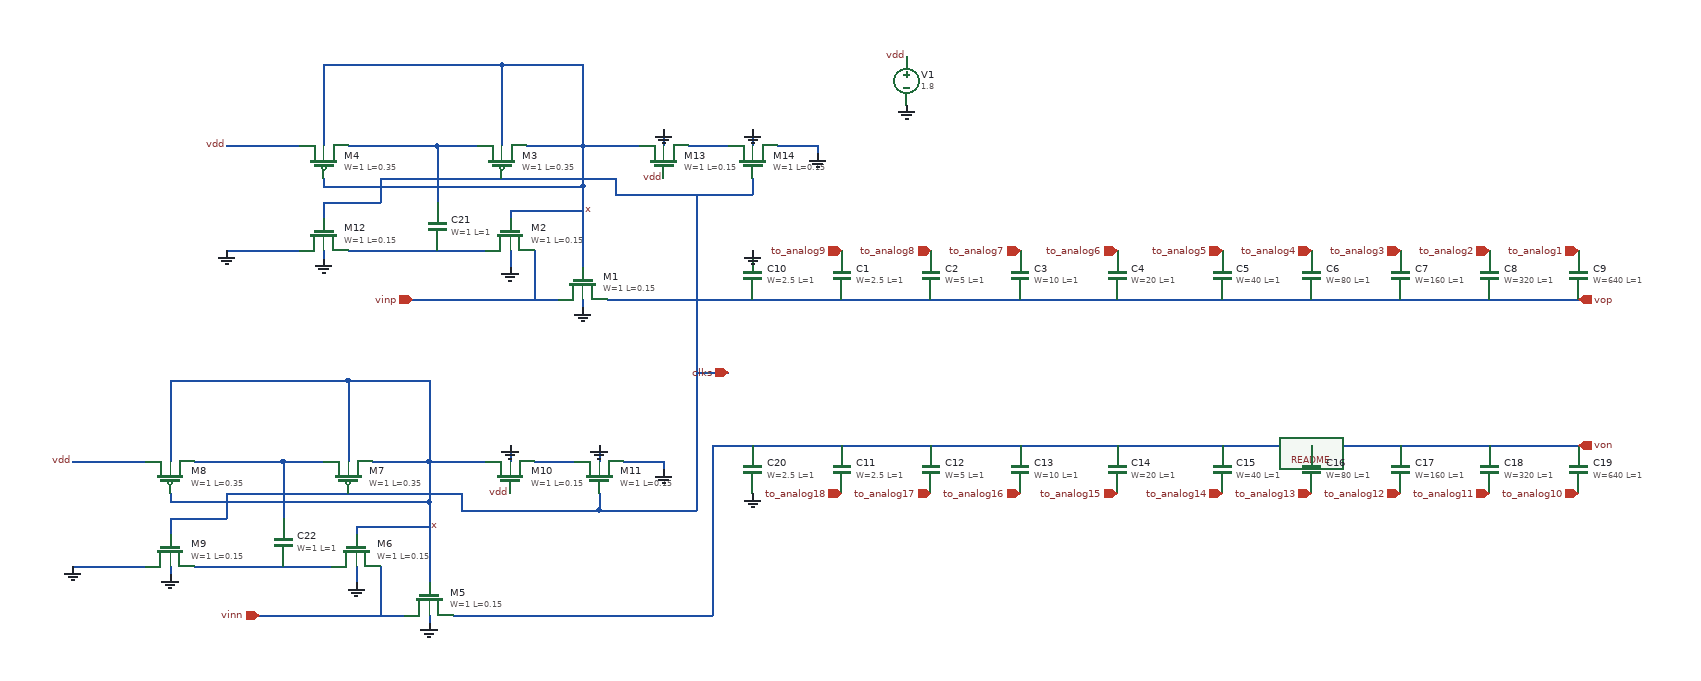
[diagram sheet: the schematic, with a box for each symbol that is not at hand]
v {xschem version=3.0.0 file_version=1.2 }
G {}
K {}
V {}
S {}
E {}
N -280 -60 -170 -60 {
lab=vop}
N -170 -60 -60 -60 {
lab=vop}
N -60 -60 50 -60 {
lab=vop}
N 50 -60 170 -60 {
lab=vop}
N 170 -60 300 -60 {
lab=vop}
N 300 -60 410 -60 {
lab=vop}
N 410 -60 520 -60 {
lab=vop}
N 520 -60 630 -60 {
lab=vop}
N 630 -60 740 -60 {
lab=vop}
N -280 120 -170 120 {
lab=von}
N -170 120 -60 120 {
lab=von}
N -60 120 50 120 {
lab=von}
N 50 120 170 120 {
lab=von}
N 170 120 300 120 {
lab=von}
N 300 120 410 120 {
lab=von}
N 410 120 520 120 {
lab=von}
N 520 120 630 120 {
lab=von}
N 630 120 740 120 {
lab=von}
N -400 -60 -280 -60 { lab=vop}
N -320 120 -280 120 { lab=von}
N -650 330 -570 330 {
lab=von}
N -680 190 -680 290 {
lab=x}
N -860 270 -800 270 {
lab=#net1}
N -860 140 -860 210 {
lab=#net2}
N -680 140 -680 190 {
lab=x}
N -860 140 -810 140 {
lab=#net2}
N -750 140 -680 140 {
lab=x}
N -970 140 -860 140 {
lab=#net2}
N -1120 140 -1030 140 {
lab=vdd}
N -970 270 -860 270 {
lab=#net1}
N -1070 270 -1030 270 {
lab=GND}
N -1120 270 -1070 270 {
lab=GND}
N -680 140 -610 140 {
lab=x}
N -550 140 -500 140 {
lab=#net3}
N -440 140 -390 140 {
lab=GND}
N -390 140 -390 150 {
lab=GND}
N -680 330 -680 340 {
lab=GND}
N -770 270 -770 290 {
lab=GND}
N -1000 270 -1000 280 {
lab=GND}
N -770 220 -770 230 {
lab=x}
N -770 220 -680 220 {
lab=x}
N -1000 180 -1000 190 {
lab=x}
N -580 120 -580 140 {
lab=GND}
N -470 120 -470 140 {
lab=GND}
N -1000 40 -1000 140 {
lab=x}
N -780 40 -780 140 {
lab=x}
N -890 330 -860 330 {
lab=vinn}
N -800 330 -710 330 {
lab=vinn}
N -740 270 -740 330 {
lab=vinn}
N -1000 40 -780 40 {
lab=x}
N -780 40 -680 40 {
lab=x}
N -680 40 -680 140 {
lab=x}
N -1000 210 -1000 230 { lab=clks}
N -1000 210 -930 210 { lab=clks}
N -930 180 -930 210 { lab=clks}
N -1000 190 -680 190 { lab=x}
N -930 180 -780 180 { lab=clks}
N -780 180 -640 180 { lab=clks}
N -640 180 -640 200 { lab=clks}
N -640 200 -470 200 { lab=clks}
N -470 180 -470 200 { lab=clks}
N -860 330 -800 330 { lab=vinn}
N -460 -60 -380 -60 {
lab=vop}
N -490 -200 -490 -100 {
lab=x}
N -670 -120 -610 -120 {
lab=#net4}
N -670 -250 -670 -180 {
lab=#net5}
N -490 -250 -490 -200 {
lab=x}
N -670 -250 -620 -250 {
lab=#net5}
N -560 -250 -490 -250 {
lab=x}
N -780 -250 -670 -250 {
lab=#net5}
N -930 -250 -840 -250 {
lab=vdd}
N -780 -120 -670 -120 {
lab=#net4}
N -880 -120 -840 -120 {
lab=GND}
N -930 -120 -880 -120 {
lab=GND}
N -490 -250 -420 -250 {
lab=x}
N -360 -250 -310 -250 {
lab=#net6}
N -250 -250 -200 -250 {
lab=GND}
N -200 -250 -200 -240 {
lab=GND}
N -490 -60 -490 -50 {
lab=GND}
N -580 -120 -580 -100 {
lab=GND}
N -810 -120 -810 -110 {
lab=GND}
N -580 -170 -580 -160 {
lab=x}
N -580 -170 -490 -170 {
lab=x}
N -810 -210 -810 -200 {
lab=x}
N -390 -270 -390 -250 {
lab=GND}
N -280 -270 -280 -250 {
lab=GND}
N -810 -350 -810 -250 {
lab=x}
N -590 -350 -590 -250 {
lab=x}
N -700 -60 -670 -60 {
lab=vinp}
N -610 -60 -520 -60 {
lab=vinp}
N -550 -120 -550 -60 {
lab=vinp}
N -810 -350 -590 -350 {
lab=x}
N -590 -350 -490 -350 {
lab=x}
N -490 -350 -490 -250 {
lab=x}
N -810 -180 -810 -160 { lab=clks}
N -810 -180 -740 -180 { lab=clks}
N -740 -210 -740 -180 { lab=clks}
N -810 -200 -490 -200 { lab=x}
N -740 -210 -590 -210 { lab=clks}
N -590 -210 -450 -210 { lab=clks}
N -450 -210 -450 -190 { lab=clks}
N -450 -190 -280 -190 { lab=clks}
N -280 -210 -280 -190 { lab=clks}
N -670 -60 -610 -60 { lab=vinp}
N -570 330 -330 330 { lab=von}
N -330 120 -330 330 { lab=von}
N -330 120 -320 120 { lab=von}
N -350 -190 -350 200 { lab=clks}
N -470 200 -350 200 { lab=clks}
N -350 30 -310 30 { lab=clks}
C {xschem_sky130/sky130_fd_pr/README.md} 410 130 0 0 {}
C {xschem_sky130/sky130_fd_pr/cap_mim_m3_1.sym} -170 -90 0 0 {name=C1 model=cap_mim_m3_1 W=2.5 L=1 MF=1 spiceprefix=X}
C {xschem_sky130/sky130_fd_pr/cap_mim_m3_1.sym} -60 -90 0 0 {name=C2 model=cap_mim_m3_1 W=5 L=1 MF=1 spiceprefix=X}
C {xschem_sky130/sky130_fd_pr/cap_mim_m3_1.sym} 50 -90 0 0 {name=C3 model=cap_mim_m3_1 W=10 L=1 MF=1 spiceprefix=X}
C {xschem_sky130/sky130_fd_pr/cap_mim_m3_1.sym} 170 -90 0 0 {name=C4 model=cap_mim_m3_1 W=20 L=1 MF=1 spiceprefix=X}
C {xschem_sky130/sky130_fd_pr/cap_mim_m3_1.sym} 300 -90 0 0 {name=C5 model=cap_mim_m3_1 W=40 L=1 MF=1 spiceprefix=X}
C {xschem_sky130/sky130_fd_pr/cap_mim_m3_1.sym} 410 -90 0 0 {name=C6 model=cap_mim_m3_1 W=80 L=1 MF=1 spiceprefix=X}
C {xschem_sky130/sky130_fd_pr/cap_mim_m3_1.sym} 520 -90 0 0 {name=C7 model=cap_mim_m3_1 W=160 L=1 MF=1 spiceprefix=X}
C {xschem_sky130/sky130_fd_pr/cap_mim_m3_1.sym} 630 -90 0 0 {name=C8 model=cap_mim_m3_1 W=320 L=1 MF=1 spiceprefix=X}
C {xschem_sky130/sky130_fd_pr/cap_mim_m3_1.sym} 740 -90 0 0 {name=C9 model=cap_mim_m3_1 W=640 L=1 MF=1 spiceprefix=X}
C {xschem_sky130/sky130_fd_pr/cap_mim_m3_1.sym} -280 -90 0 0 {name=C10 model=cap_mim_m3_1 W=2.5 L=1 MF=1 spiceprefix=X}
C {xschem_sky130/sky130_fd_pr/cap_mim_m3_1.sym} -170 150 0 0 {name=C11 model=cap_mim_m3_1 W=2.5 L=1 MF=1 spiceprefix=X}
C {xschem_sky130/sky130_fd_pr/cap_mim_m3_1.sym} -60 150 0 0 {name=C12 model=cap_mim_m3_1 W=5 L=1 MF=1 spiceprefix=X}
C {xschem_sky130/sky130_fd_pr/cap_mim_m3_1.sym} 50 150 0 0 {name=C13 model=cap_mim_m3_1 W=10 L=1 MF=1 spiceprefix=X}
C {xschem_sky130/sky130_fd_pr/cap_mim_m3_1.sym} 170 150 0 0 {name=C14 model=cap_mim_m3_1 W=20 L=1 MF=1 spiceprefix=X}
C {xschem_sky130/sky130_fd_pr/cap_mim_m3_1.sym} 300 150 0 0 {name=C15 model=cap_mim_m3_1 W=40 L=1 MF=1 spiceprefix=X}
C {xschem_sky130/sky130_fd_pr/cap_mim_m3_1.sym} 410 150 0 0 {name=C16 model=cap_mim_m3_1 W=80 L=1 MF=1 spiceprefix=X}
C {xschem_sky130/sky130_fd_pr/cap_mim_m3_1.sym} 520 150 0 0 {name=C17 model=cap_mim_m3_1 W=160 L=1 MF=1 spiceprefix=X}
C {xschem_sky130/sky130_fd_pr/cap_mim_m3_1.sym} 630 150 0 0 {name=C18 model=cap_mim_m3_1 W=320 L=1 MF=1 spiceprefix=X}
C {xschem_sky130/sky130_fd_pr/cap_mim_m3_1.sym} 740 150 0 0 {name=C19 model=cap_mim_m3_1 W=640 L=1 MF=1 spiceprefix=X}
C {xschem_sky130/sky130_fd_pr/cap_mim_m3_1.sym} -280 150 0 0 {name=C20 model=cap_mim_m3_1 W=2.5 L=1 MF=1 spiceprefix=X}
C {ipin.sym} -170 -120 0 0 {name=p2 lab=to_analog9}
C {ipin.sym} -60 -120 0 0 {name=p3 lab=to_analog8}
C {ipin.sym} 50 -120 0 0 {name=p4 lab=to_analog7}
C {ipin.sym} 170 -120 0 0 {name=p5 lab=to_analog6}
C {ipin.sym} 300 -120 0 0 {name=p6 lab=to_analog5}
C {ipin.sym} 410 -120 0 0 {name=p8 lab=to_analog4}
C {ipin.sym} 520 -120 0 0 {name=p9 lab=to_analog3}
C {ipin.sym} 630 -120 0 0 {name=p10 lab=to_analog2}
C {ipin.sym} 740 -120 0 0 {name=p11 lab=to_analog1}
C {ipin.sym} -170 180 0 0 {name=p13 lab=to_analog18}
C {ipin.sym} -60 180 0 0 {name=p14 lab=to_analog17}
C {ipin.sym} 50 180 0 0 {name=p15 lab=to_analog16}
C {ipin.sym} 170 180 0 0 {name=p16 lab=to_analog15}
C {ipin.sym} 300 180 0 0 {name=p17 lab=to_analog14}
C {ipin.sym} 410 180 0 0 {name=p18 lab=to_analog13}
C {ipin.sym} 520 180 0 0 {name=p19 lab=to_analog12}
C {ipin.sym} 630 180 0 0 {name=p20 lab=to_analog11}
C {ipin.sym} 740 180 0 0 {name=p21 lab=to_analog10}
C {opin.sym} 740 -60 0 0 {name=p24 lab=vop}
C {opin.sym} 740 120 0 0 {name=p25 lab=von}
C {ipin.sym} -890 330 0 0 {name=p26 lab=vinn}
C {gnd.sym} -280 180 0 0 {name=l1 lab=GND}
C {gnd.sym} -280 -120 2 0 {name=l2 lab=GND}
C {ipin.sym} -310 30 2 0 {name=p22 lab=clks}
C {xschem_sky130/sky130_fd_pr/nfet_01v8_lvt.sym} -680 310 1 0 {name=M5
L=0.15
W=1
nf=1
mult=1
ad="'int((nf+1)/2) * W/nf * 0.29'" 
pd="'2*int((nf+1)/2) * (W/nf + 0.29)'"
as="'int((nf+2)/2) * W/nf * 0.29'" 
ps="'2*int((nf+2)/2) * (W/nf + 0.29)'"
nrd="'0.29 / W'" nrs="'0.29 / W'"
sa=0 sb=0 sd=0
model=nfet_01v8_lvt
spiceprefix=X
}
C {xschem_sky130/sky130_fd_pr/nfet_01v8_lvt.sym} -770 250 1 0 {name=M6
L=0.15
W=1
nf=1
mult=1
ad="'int((nf+1)/2) * W/nf * 0.29'" 
pd="'2*int((nf+1)/2) * (W/nf + 0.29)'"
as="'int((nf+2)/2) * W/nf * 0.29'" 
ps="'2*int((nf+2)/2) * (W/nf + 0.29)'"
nrd="'0.29 / W'" nrs="'0.29 / W'"
sa=0 sb=0 sd=0
model=nfet_01v8_lvt
spiceprefix=X
}
C {xschem_sky130/sky130_fd_pr/cap_mim_m3_1.sym} -860 240 0 0 {name=C22 model=cap_mim_m3_1 W=1 L=1 MF=1 spiceprefix=X}
C {xschem_sky130/sky130_fd_pr/pfet_01v8_lvt.sym} -780 160 3 0 {name=M7
L=0.35
W=1
nf=1
mult=1
ad="'int((nf+1)/2) * W/nf * 0.29'" 
pd="'2*int((nf+1)/2) * (W/nf + 0.29)'"
as="'int((nf+2)/2) * W/nf * 0.29'" 
ps="'2*int((nf+2)/2) * (W/nf + 0.29)'"
nrd="'0.29 / W'" nrs="'0.29 / W'"
sa=0 sb=0 sd=0
model=pfet_01v8_lvt
spiceprefix=X
}
C {xschem_sky130/sky130_fd_pr/pfet_01v8_lvt.sym} -1000 160 3 0 {name=M8
L=0.35
W=1
nf=1
mult=1
ad="'int((nf+1)/2) * W/nf * 0.29'" 
pd="'2*int((nf+1)/2) * (W/nf + 0.29)'"
as="'int((nf+2)/2) * W/nf * 0.29'" 
ps="'2*int((nf+2)/2) * (W/nf + 0.29)'"
nrd="'0.29 / W'" nrs="'0.29 / W'"
sa=0 sb=0 sd=0
model=pfet_01v8_lvt
spiceprefix=X
}
C {xschem_sky130/sky130_fd_pr/nfet_01v8_lvt.sym} -1000 250 1 0 {name=M9
L=0.15
W=1
nf=1
mult=1
ad="'int((nf+1)/2) * W/nf * 0.29'" 
pd="'2*int((nf+1)/2) * (W/nf + 0.29)'"
as="'int((nf+2)/2) * W/nf * 0.29'" 
ps="'2*int((nf+2)/2) * (W/nf + 0.29)'"
nrd="'0.29 / W'" nrs="'0.29 / W'"
sa=0 sb=0 sd=0
model=nfet_01v8_lvt
spiceprefix=X
}
C {xschem_sky130/sky130_fd_pr/nfet_01v8_lvt.sym} -580 160 3 0 {name=M10
L=0.15
W=1
nf=1
mult=1
ad="'int((nf+1)/2) * W/nf * 0.29'" 
pd="'2*int((nf+1)/2) * (W/nf + 0.29)'"
as="'int((nf+2)/2) * W/nf * 0.29'" 
ps="'2*int((nf+2)/2) * (W/nf + 0.29)'"
nrd="'0.29 / W'" nrs="'0.29 / W'"
sa=0 sb=0 sd=0
model=nfet_01v8_lvt
spiceprefix=X
}
C {xschem_sky130/sky130_fd_pr/nfet_01v8_lvt.sym} -470 160 3 0 {name=M11
L=0.15
W=1
nf=1
mult=1
ad="'int((nf+1)/2) * W/nf * 0.29'" 
pd="'2*int((nf+1)/2) * (W/nf + 0.29)'"
as="'int((nf+2)/2) * W/nf * 0.29'" 
ps="'2*int((nf+2)/2) * (W/nf + 0.29)'"
nrd="'0.29 / W'" nrs="'0.29 / W'"
sa=0 sb=0 sd=0
model=nfet_01v8_lvt
spiceprefix=X
}
C {gnd.sym} -390 150 0 0 {name=l5 lab=GND}
C {gnd.sym} -1120 270 0 0 {name=l6 lab=GND}
C {gnd.sym} -770 290 0 0 {name=l7 lab=GND}
C {gnd.sym} -1000 280 0 0 {name=l8 lab=GND}
C {gnd.sym} -580 120 2 0 {name=l15 lab=GND}
C {gnd.sym} -470 120 2 0 {name=l16 lab=GND}
C {lab_pin.sym} -680 220 2 0 {name=l18 sig_type=std_logic lab=x}
C {lab_pin.sym} -1120 140 0 0 {name=l24 sig_type=std_logic lab=vdd}
C {lab_pin.sym} -580 180 0 0 {name=l25 sig_type=std_logic lab=vdd}
C {gnd.sym} -680 340 0 0 {name=V6 value=-1.8}
C {vsource.sym} -90 -330 0 0 {name=V1 value=1.8}
C {gnd.sym} -90 -300 0 0 {name=l3 lab=GND}
C {lab_pin.sym} -90 -360 0 0 {name=l23 sig_type=std_logic lab=vdd}
C {ipin.sym} -700 -60 0 0 {name=p7 lab=vinp}
C {xschem_sky130/sky130_fd_pr/nfet_01v8_lvt.sym} -490 -80 1 0 {name=M1
L=0.15
W=1
nf=1
mult=1
ad="'int((nf+1)/2) * W/nf * 0.29'" 
pd="'2*int((nf+1)/2) * (W/nf + 0.29)'"
as="'int((nf+2)/2) * W/nf * 0.29'" 
ps="'2*int((nf+2)/2) * (W/nf + 0.29)'"
nrd="'0.29 / W'" nrs="'0.29 / W'"
sa=0 sb=0 sd=0
model=nfet_01v8_lvt
spiceprefix=X
}
C {xschem_sky130/sky130_fd_pr/nfet_01v8_lvt.sym} -580 -140 1 0 {name=M2
L=0.15
W=1
nf=1
mult=1
ad="'int((nf+1)/2) * W/nf * 0.29'" 
pd="'2*int((nf+1)/2) * (W/nf + 0.29)'"
as="'int((nf+2)/2) * W/nf * 0.29'" 
ps="'2*int((nf+2)/2) * (W/nf + 0.29)'"
nrd="'0.29 / W'" nrs="'0.29 / W'"
sa=0 sb=0 sd=0
model=nfet_01v8_lvt
spiceprefix=X
}
C {xschem_sky130/sky130_fd_pr/cap_mim_m3_1.sym} -670 -150 0 0 {name=C21 model=cap_mim_m3_1 W=1 L=1 MF=1 spiceprefix=X}
C {xschem_sky130/sky130_fd_pr/pfet_01v8_lvt.sym} -590 -230 3 0 {name=M3
L=0.35
W=1
nf=1
mult=1
ad="'int((nf+1)/2) * W/nf * 0.29'" 
pd="'2*int((nf+1)/2) * (W/nf + 0.29)'"
as="'int((nf+2)/2) * W/nf * 0.29'" 
ps="'2*int((nf+2)/2) * (W/nf + 0.29)'"
nrd="'0.29 / W'" nrs="'0.29 / W'"
sa=0 sb=0 sd=0
model=pfet_01v8_lvt
spiceprefix=X
}
C {xschem_sky130/sky130_fd_pr/pfet_01v8_lvt.sym} -810 -230 3 0 {name=M4
L=0.35
W=1
nf=1
mult=1
ad="'int((nf+1)/2) * W/nf * 0.29'" 
pd="'2*int((nf+1)/2) * (W/nf + 0.29)'"
as="'int((nf+2)/2) * W/nf * 0.29'" 
ps="'2*int((nf+2)/2) * (W/nf + 0.29)'"
nrd="'0.29 / W'" nrs="'0.29 / W'"
sa=0 sb=0 sd=0
model=pfet_01v8_lvt
spiceprefix=X
}
C {xschem_sky130/sky130_fd_pr/nfet_01v8_lvt.sym} -810 -140 1 0 {name=M12
L=0.15
W=1
nf=1
mult=1
ad="'int((nf+1)/2) * W/nf * 0.29'" 
pd="'2*int((nf+1)/2) * (W/nf + 0.29)'"
as="'int((nf+2)/2) * W/nf * 0.29'" 
ps="'2*int((nf+2)/2) * (W/nf + 0.29)'"
nrd="'0.29 / W'" nrs="'0.29 / W'"
sa=0 sb=0 sd=0
model=nfet_01v8_lvt
spiceprefix=X
}
C {xschem_sky130/sky130_fd_pr/nfet_01v8_lvt.sym} -390 -230 3 0 {name=M13
L=0.15
W=1
nf=1
mult=1
ad="'int((nf+1)/2) * W/nf * 0.29'" 
pd="'2*int((nf+1)/2) * (W/nf + 0.29)'"
as="'int((nf+2)/2) * W/nf * 0.29'" 
ps="'2*int((nf+2)/2) * (W/nf + 0.29)'"
nrd="'0.29 / W'" nrs="'0.29 / W'"
sa=0 sb=0 sd=0
model=nfet_01v8_lvt
spiceprefix=X
}
C {xschem_sky130/sky130_fd_pr/nfet_01v8_lvt.sym} -280 -230 3 0 {name=M14
L=0.15
W=1
nf=1
mult=1
ad="'int((nf+1)/2) * W/nf * 0.29'" 
pd="'2*int((nf+1)/2) * (W/nf + 0.29)'"
as="'int((nf+2)/2) * W/nf * 0.29'" 
ps="'2*int((nf+2)/2) * (W/nf + 0.29)'"
nrd="'0.29 / W'" nrs="'0.29 / W'"
sa=0 sb=0 sd=0
model=nfet_01v8_lvt
spiceprefix=X
}
C {gnd.sym} -200 -240 0 0 {name=l4 lab=GND}
C {gnd.sym} -930 -120 0 0 {name=l9 lab=GND}
C {gnd.sym} -580 -100 0 0 {name=l10 lab=GND}
C {gnd.sym} -810 -110 0 0 {name=l11 lab=GND}
C {gnd.sym} -390 -270 2 0 {name=l12 lab=GND}
C {gnd.sym} -280 -270 2 0 {name=l13 lab=GND}
C {lab_pin.sym} -490 -170 2 0 {name=l14 sig_type=std_logic lab=x}
C {lab_pin.sym} -930 -250 0 0 {name=l17 sig_type=std_logic lab=vdd}
C {lab_pin.sym} -390 -210 0 0 {name=l19 sig_type=std_logic lab=vdd}
C {gnd.sym} -490 -50 0 0 {name=V2 value=-1.8}
